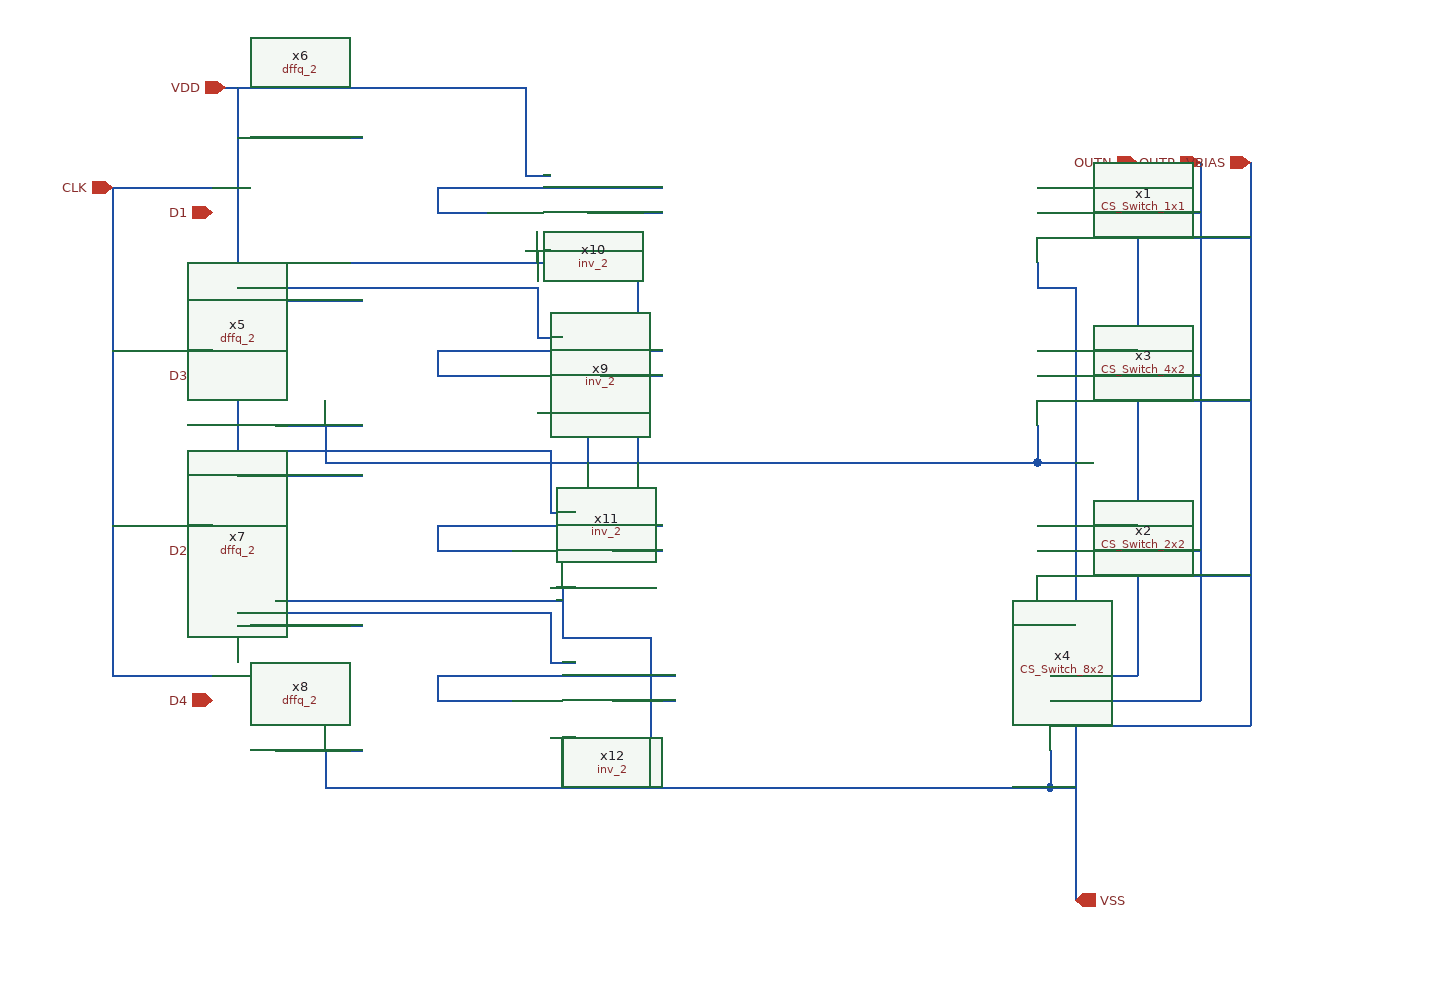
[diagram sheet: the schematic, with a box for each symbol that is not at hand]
v {xschem version=3.4.5 file_version=1.2
}
G {}
K {}
V {}
S {}
E {}
N 890 -50 1070 -50 {
lab=#net1}
N 890 -180 1070 -180 {
lab=#net2}
N 890 90 1070 90 {
lab=#net3}
N 890 210 1080 210 {
lab=#net4}
N 1370 -120 1370 -100 {
lab=VSS}
N 1370 10 1370 40 {
lab=VSS}
N 800 40 1370 40 {
lab=VSS}
N 1370 150 1370 170 {
lab=VSS}
N 1380 270 1380 300 {
lab=VSS}
N 800 300 1380 300 {
lab=VSS}
N 1020 -30 1070 -30 {
lab=#net5}
N 890 -30 940 -30 {
lab=#net1}
N 890 -50 890 -30 {
lab=#net1}
N 1010 -160 1070 -160 {
lab=#net6}
N 890 -160 930 -160 {
lab=#net2}
N 890 -180 890 -160 {
lab=#net2}
N 1030 110 1070 110 {
lab=#net7}
N 890 90 890 110 {
lab=#net3}
N 890 110 950 110 {
lab=#net3}
N 1030 230 1080 230 {
lab=#net8}
N 890 210 890 230 {
lab=#net4}
N 890 230 950 230 {
lab=#net4}
N 1370 -100 1400 -100 {
lab=VSS}
N 1400 -100 1400 390 {
lab=VSS}
N 1370 40 1400 40 {
lab=VSS}
N 1370 170 1400 170 {
lab=VSS}
N 1380 300 1400 300 {
lab=VSS}
N 1450 -200 1450 -180 {
lab=OUTN}
N 1540 -200 1540 250 {
lab=VBIAS}
N 1380 250 1540 250 {
lab=VBIAS}
N 1370 130 1540 130 {
lab=VBIAS}
N 1370 -10 1540 -10 {
lab=VBIAS}
N 1370 -140 1540 -140 {
lab=VBIAS}
N 720 -260 790 -260 {
lab=VDD}
N 730 -260 730 -90 {
lab=VDD}
N 730 -90 730 180 {
lab=VDD}
N 630 -180 710 -180 {
lab=CLK}
N 630 -180 630 210 {
lab=CLK}
N 630 210 710 210 {
lab=CLK}
N 630 -50 710 -50 {
lab=CLK}
N 630 90 710 90 {
lab=CLK}
N 790 -260 940 -260 {
lab=VDD}
N 760 -220 830 -220 {
lab=VDD}
N 960 -190 980 -190 {
lab=VDD}
N 960 -130 980 -130 {
lab=VSS}
N 770 -120 830 -120 {
lab=VSS}
N 760 -120 770 -120 {
lab=VSS}
N 760 -90 830 -90 {
lab=VDD}
N 760 10 830 10 {
lab=VSS}
N 760 50 830 50 {
lab=VDD}
N 970 0 990 -0 {
lab=VSS}
N 970 -60 990 -60 {
lab=VDD}
N 980 80 1000 80 {
lab=VDD}
N 980 140 1000 140 {
lab=VSS}
N 760 150 830 150 {
lab=VSS}
N 760 170 830 170 {
lab=VDD}
N 760 270 830 270 {
lab=VSS}
N 980 260 1000 260 {
lab=VSS}
N 980 200 1000 200 {
lab=VDD}
N 730 170 760 170 {
lab=VDD}
N 730 50 760 50 {
lab=VDD}
N 730 -90 760 -90 {
lab=VDD}
N 730 -220 760 -220 {
lab=VDD}
N 960 -260 960 -190 {
lab=VDD}
N 940 -260 960 -260 {
lab=VDD}
N 970 -100 970 -60 {
lab=VDD}
N 730 -100 970 -100 {
lab=VDD}
N 980 30 980 80 {
lab=VDD}
N 730 30 980 30 {
lab=VDD}
N 980 160 980 200 {
lab=VDD}
N 730 160 980 160 {
lab=VDD}
N 800 270 800 300 {
lab=VSS}
N 990 260 990 300 {
lab=VSS}
N 990 140 990 180 {
lab=VSS}
N 990 180 1060 180 {
lab=VSS}
N 1060 180 1060 300 {
lab=VSS}
N 830 150 990 150 {
lab=VSS}
N 800 10 800 40 {
lab=VSS}
N 990 -0 1010 0 {
lab=VSS}
N 1010 0 1010 40 {
lab=VSS}
N 830 -120 1050 -120 {
lab=VSS}
N 1050 -120 1050 40 {
lab=VSS}
N 970 -130 970 -120 {
lab=VSS}
N 1500 -200 1500 230 {
lab=OUTP}
N 1450 -180 1450 210 {
lab=OUTN}
N 1370 -160 1500 -160 {
lab=OUTP}
N 1370 110 1500 110 {
lab=OUTP}
N 1370 -30 1500 -30 {
lab=OUTP}
N 1380 230 1500 230 {
lab=OUTP}
N 1380 210 1450 210 {
lab=OUTN}
N 1370 90 1450 90 {
lab=OUTN}
N 1370 -50 1450 -50 {
lab=OUTN}
N 1370 -180 1450 -180 {
lab=OUTN}
C {ipin.sym} 710 -160 0 0 {name=p1 lab=D1}
C {ipin.sym} 710 110 0 0 {name=p2 lab=D2}
C {ipin.sym} 710 -30 0 0 {name=p3 lab=D3}
C {ipin.sym} 710 230 0 0 {name=p4 lab=D4}
C {opin.sym} 1500 -200 1 1 {name=p6 lab=OUTP}
C {opin.sym} 1450 -200 1 1 {name=p7 lab=OUTN}
C {opin.sym} 1540 -200 2 1 {name=p8 lab=VBIAS}
C {ipin.sym} 630 -180 0 0 {name=p5 lab=CLK}
C {opin.sym} 720 -260 0 1 {name=p10 lab=VDD}
C {opin.sym} 1400 390 0 0 {name=p9 lab=VSS}
C {gf180mcuc-stdcells/dffq_2.sym} 800 -40 0 0 {name=x5 VDD=VDD VNW=VNW VPW=VPW VSS=VSS prefix=gf180mcu_fd_sc_mcu7t5v0__ }
C {gf180mcuc-stdcells/dffq_2.sym} 800 -170 0 0 {name=x6 VDD=VDD VNW=VNW VPW=VPW VSS=VSS prefix=gf180mcu_fd_sc_mcu7t5v0__ }
C {gf180mcuc-stdcells/dffq_2.sym} 800 100 0 0 {name=x7 VDD=VDD VNW=VNW VPW=VPW VSS=VSS prefix=gf180mcu_fd_sc_mcu7t5v0__ }
C {gf180mcuc-stdcells/dffq_2.sym} 800 220 0 0 {name=x8 VDD=VDD VNW=VNW VPW=VPW VSS=VSS prefix=gf180mcu_fd_sc_mcu7t5v0__ }
C {gf180mcuc-stdcells/inv_2.sym} 980 -30 0 0 {name=x9 VDD=VDD VNW=VNW VPW=VPW VSS=VSS prefix=gf180mcu_fd_sc_mcu7t5v0__ }
C {gf180mcuc-stdcells/inv_2.sym} 970 -160 0 0 {name=x10 VDD=VDD VNW=VNW VPW=VPW VSS=VSS prefix=gf180mcu_fd_sc_mcu7t5v0__ }
C {gf180mcuc-stdcells/inv_2.sym} 990 110 0 0 {name=x11 VDD=VDD VNW=VNW VPW=VPW VSS=VSS prefix=gf180mcu_fd_sc_mcu7t5v0__ }
C {gf180mcuc-stdcells/inv_2.sym} 990 230 0 0 {name=x12 VDD=VDD VNW=VNW VPW=VPW VSS=VSS prefix=gf180mcu_fd_sc_mcu7t5v0__ }
C {CS_Switch_1x1.sym} 1220 -150 0 0 {name=x1}
C {CS_Switch_2x2.sym} 1220 120 0 0 {name=x2}
C {CS_Switch_4x2.sym} 1220 -20 0 0 {name=x3}
C {CS_Switch_8x2.sym} 1230 240 0 0 {name=x4}
